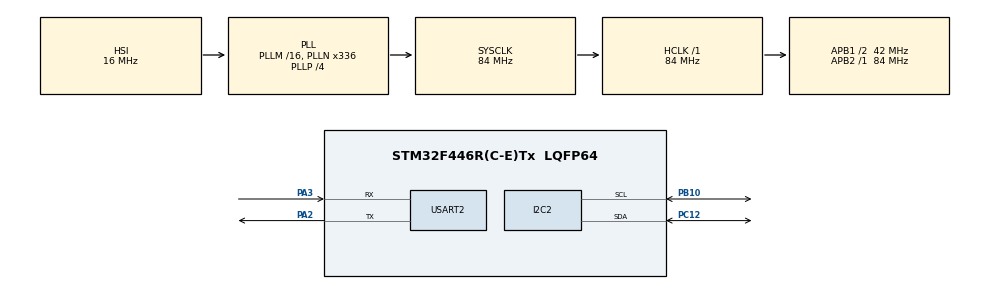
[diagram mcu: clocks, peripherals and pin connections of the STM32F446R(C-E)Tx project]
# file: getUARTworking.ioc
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Mcu.Family=STM32F4
Mcu.Name=STM32F446R(C-E)Tx
Mcu.Package=LQFP64
NVIC.PriorityGroup=NVIC_PRIORITYGROUP_0
PA2.Mode=Asynchronous
PA2.Signal=USART2_TX
PA3.Mode=Asynchronous
PA3.Signal=USART2_RX
PB10.Mode=I2C
PB10.Signal=I2C2_SCL
PC12.Mode=I2C
PC12.Signal=I2C2_SDA
ProjectManager.HeapSize=0x200
ProjectManager.StackSize=0x400
ProjectManager.TargetToolchain=STM32CubeIDE
RCC.AHBFreq_Value=84000000
RCC.APB1CLKDivider=RCC_HCLK_DIV2
RCC.APB1Freq_Value=42000000
RCC.APB1TimFreq_Value=84000000
RCC.APB2Freq_Value=84000000
RCC.APB2TimFreq_Value=84000000
RCC.CortexFreq_Value=84000000
RCC.FLatency-AdvancedSettings=FLASH_LATENCY_2
RCC.HCLKFreq_Value=84000000
RCC.HSE_VALUE=8000000
RCC.HSI_VALUE=16000000
RCC.LSE_VALUE=32768
RCC.PLLN=336
RCC.PLLP=RCC_PLLP_DIV4
RCC.SYSCLKFreq_VALUE=84000000
RCC.SYSCLKSource=RCC_SYSCLKSOURCE_PLLCLK
RCC.USBFreq_Value=168000000
RCC.VCOOutputFreq_Value=336000000
USART2.VirtualMode=VM_ASYNC
board=NUCLEO-F446RE

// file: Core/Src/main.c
/* USER CODE BEGIN Header */
/**
  ******************************************************************************
  * @file           : main.c
  * @brief          : Main program body
  ******************************************************************************
  * @attention
  *
  * Copyright (c) 2022 STMicroelectronics.
  * All rights reserved.
  *
  * This software is licensed under terms that can be found in the LICENSE file
  * in the root directory of this software component.
  * If no LICENSE file comes with this software, it is provided AS-IS.
  *
  ******************************************************************************
  */
/* USER CODE END Header */
#include "main.h"
#include "stm32F4xx_hal.h"
#include "vl53l0x_api.h"
#include "bretts_helper.h"
#include "helpful_i2c.h"

I2C_HandleTypeDef hi2c2;
UART_HandleTypeDef huart2;

/* USER CODE BEGIN PV */
VL53L0X_Dev_t devs[2];
VL53L0_DEV	Dev;
int distances[2];
int howManyDevs = 2;
int brett_status = 0;
/* USER CODE END PV */

#define GPIO_read 0x41
#define GPIO_write 0x40

#define GPIO_All_Off 0x00
#define GPIO_P0_On 0x01
#define GPIO_P1_On 0x02
#define GPIO_P2_On 0x04
#define GPIO_P3_On 0x08
#define GPIO_P4_On 0x10
#define GPIO_P5_On 0x20
#define GPIO_P6_On 0x40
#define GPIO_P7_On 0x80

void SystemClock_Config(void);
static void MX_GPIO_Init(void);
static void MX_I2C2_Init(void);
static void MX_USART2_UART_Init(void);

/* USER CODE BEGIN 0 */
#define PUTCHAR_PROTOTYPE int __io_putchar(int ch)

PUTCHAR_PROTOTYPE
{
	HAL_UART_Transmit(&huart2, (uint8_t*)&ch, 1, 0xFFFF);
	return ch;
}

/* USER CODE END 0 */

int main(void)
{

	/* MCU Configuration--------------------------------------------------------*/

	/* Reset of all peripherals, Initializes the Flash interface and the Systick. */
	HAL_Init();

	/* Configure the system clock */
	SystemClock_Config();

	/* Initialize all configured peripherals */
	MX_GPIO_Init();
	MX_I2C2_Init();
	MX_USART2_UART_Init();

	// init IRs
	brett_status = Brett_IR_InitIrSensor(devs, &hi2c2, howManyDevs);
	if (brett_status != 0)
		printf("brett status %i\n\r", brett_status);

	/* Infinite loop */
	/* USER CODE BEGIN WHILE */
	while (1)
	{
		brett_status = Brett_IR_StartMulti(devs, distances, howManyDevs);
		if (brett_status != 0)
			printf("brett status %i\n\r", brett_status);
		printf("distance 1 %i\n\r", distances[0]);
		printf("distance 2 %i\n\r", distances[1]);
		printf("\n\r");
		HAL_Delay(1000);
	}
	/* USER CODE END 3 */
}

void SystemClock_Config(void)
{
  RCC_OscInitTypeDef RCC_OscInitStruct = {0};
  RCC_ClkInitTypeDef RCC_ClkInitStruct = {0};

  /** Configure the main internal regulator output voltage
  */
  __HAL_RCC_PWR_CLK_ENABLE();
  __HAL_PWR_VOLTAGESCALING_CONFIG(PWR_REGULATOR_VOLTAGE_SCALE3);
  /** Initializes the RCC Oscillators according to the specified parameters
  * in the RCC_OscInitTypeDef structure.
  */
  RCC_OscInitStruct.OscillatorType = RCC_OSCILLATORTYPE_HSI;
  RCC_OscInitStruct.HSIState = RCC_HSI_ON;
  RCC_OscInitStruct.HSICalibrationValue = RCC_HSICALIBRATION_DEFAULT;
  RCC_OscInitStruct.PLL.PLLState = RCC_PLL_ON;
  RCC_OscInitStruct.PLL.PLLSource = RCC_PLLSOURCE_HSI;
  RCC_OscInitStruct.PLL.PLLM = 16;
  RCC_OscInitStruct.PLL.PLLN = 336;
  RCC_OscInitStruct.PLL.PLLP = RCC_PLLP_DIV4;
  RCC_OscInitStruct.PLL.PLLQ = 2;
  RCC_OscInitStruct.PLL.PLLR = 2;
  if (HAL_RCC_OscConfig(&RCC_OscInitStruct) != HAL_OK)
  {
    Error_Handler();
  }
  /** Initializes the CPU, AHB and APB buses clocks
  */
  RCC_ClkInitStruct.ClockType = RCC_CLOCKTYPE_HCLK|RCC_CLOCKTYPE_SYSCLK
                              |RCC_CLOCKTYPE_PCLK1|RCC_CLOCKTYPE_PCLK2;
  RCC_ClkInitStruct.SYSCLKSource = RCC_SYSCLKSOURCE_PLLCLK;
  RCC_ClkInitStruct.AHBCLKDivider = RCC_SYSCLK_DIV1;
  RCC_ClkInitStruct.APB1CLKDivider = RCC_HCLK_DIV2;
  RCC_ClkInitStruct.APB2CLKDivider = RCC_HCLK_DIV1;

  if (HAL_RCC_ClockConfig(&RCC_ClkInitStruct, FLASH_LATENCY_2) != HAL_OK)
  {
    Error_Handler();
  }
}

static void MX_I2C2_Init(void)
{

  hi2c2.Instance = I2C2;
  hi2c2.Init.ClockSpeed = 100000;
  hi2c2.Init.DutyCycle = I2C_DUTYCYCLE_2;
  hi2c2.Init.OwnAddress1 = 0;
  hi2c2.Init.AddressingMode = I2C_ADDRESSINGMODE_7BIT;
  hi2c2.Init.DualAddressMode = I2C_DUALADDRESS_DISABLE;
  hi2c2.Init.OwnAddress2 = 0;
  hi2c2.Init.GeneralCallMode = I2C_GENERALCALL_DISABLE;
  hi2c2.Init.NoStretchMode = I2C_NOSTRETCH_DISABLE;
  if (HAL_I2C_Init(&hi2c2) != HAL_OK)
  {
    Error_Handler();
  }

}

static void MX_USART2_UART_Init(void)
{

  huart2.Instance = USART2;
  huart2.Init.BaudRate = 115200;
  huart2.Init.WordLength = UART_WORDLENGTH_8B;
  huart2.Init.StopBits = UART_STOPBITS_1;
  huart2.Init.Parity = UART_PARITY_NONE;
  huart2.Init.Mode = UART_MODE_TX_RX;
  huart2.Init.HwFlowCtl = UART_HWCONTROL_NONE;
  huart2.Init.OverSampling = UART_OVERSAMPLING_16;
  if (HAL_UART_Init(&huart2) != HAL_OK)
  {
    Error_Handler();
  }

}

static void MX_GPIO_Init(void)
{
	GPIO_InitTypeDef GPIO_InitStruct = {0};

	/* GPIO Ports Clock Enable */
	__HAL_RCC_GPIOA_CLK_ENABLE();
	__HAL_RCC_GPIOB_CLK_ENABLE();
	__HAL_RCC_GPIOC_CLK_ENABLE();

	/*Configure GPIO pin Output Level */
	HAL_GPIO_WritePin(GPIOA, GPIO_PIN_7, GPIO_PIN_RESET);
	HAL_GPIO_WritePin(GPIOA, GPIO_PIN_8, GPIO_PIN_RESET);

	// d1pin
	GPIO_InitStruct.Pin = GPIO_PIN_7;
	GPIO_InitStruct.Mode = GPIO_MODE_OUTPUT_PP;
	GPIO_InitStruct.Pull = GPIO_NOPULL;
	GPIO_InitStruct.Speed = GPIO_SPEED_FREQ_LOW;
	HAL_GPIO_Init(GPIOA, &GPIO_InitStruct);

	// d2pin
	GPIO_InitStruct.Pin = GPIO_PIN_8;
	GPIO_InitStruct.Mode = GPIO_MODE_OUTPUT_PP;
	GPIO_InitStruct.Pull = GPIO_NOPULL;
	GPIO_InitStruct.Speed = GPIO_SPEED_FREQ_LOW;
	HAL_GPIO_Init(GPIOA, &GPIO_InitStruct);

}

void Error_Handler(void)
{
  __disable_irq();
  while (1)
  {
  }
}
